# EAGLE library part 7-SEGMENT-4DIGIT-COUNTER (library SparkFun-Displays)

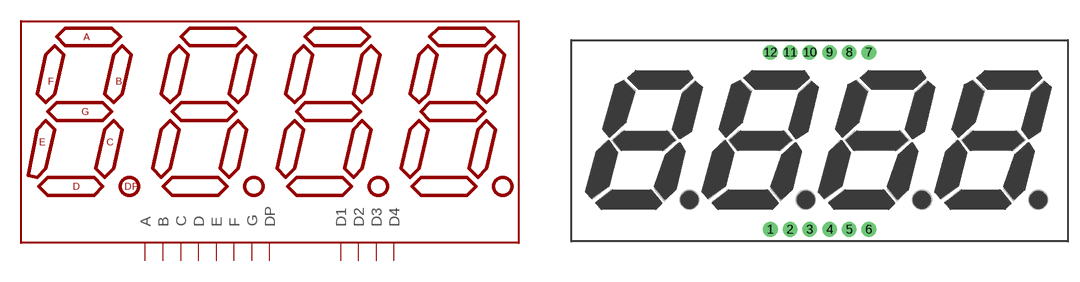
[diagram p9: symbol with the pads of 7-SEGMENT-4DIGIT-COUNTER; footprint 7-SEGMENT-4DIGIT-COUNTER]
Designator prefix -

## 7-SEGMENT-4DIGIT-COUNTERPTH  [7-SEGMENT-4DIGIT-COUNTER]
1  E
2  D
3  DP
4  C
5  G
6  D4
7  B
8  D3
9  D2
10  F
11  A
12  D1

## Footprint 7-SEGMENT-4DIGIT-COUNTER (pad centres in mm)
drill 0.9 pad 1.88: 1 -6.35,-11.43; 2 -3.81,-11.43; 3 -1.27,-11.43; 4 1.27,-11.43; 5 3.81,-11.43; 6 6.35,-11.43; 7 6.35,11.43; 8 3.81,11.43; 9 1.27,11.43; 10 -1.27,11.43; 11 -3.81,11.43; 12 -6.35,11.43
